VERSION 5.7 ;
  NOWIREEXTENSIONATPIN ON ;
  DIVIDERCHAR "/" ;
  BUSBITCHARS "[]" ;
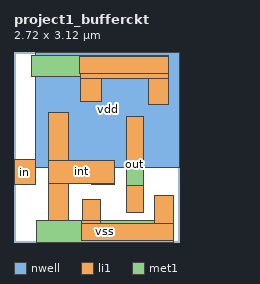
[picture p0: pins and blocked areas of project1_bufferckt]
MACRO project1_bufferckt
  CLASS BLOCK ;
  FOREIGN project1_bufferckt ;
  ORIGIN -2.150 2.430 ;
  SIZE 2.720 BY 3.120 ;
  PIN vdd
    ANTENNADIFFAREA 0.959400 ;
    PORT
      LAYER nwell ;
        RECT 2.510 -1.200 4.870 0.690 ;
      LAYER li1 ;
        RECT 3.230 0.340 4.690 0.620 ;
        RECT 3.240 0.260 4.690 0.340 ;
        RECT 3.240 -0.120 3.590 0.260 ;
        RECT 4.360 -0.180 4.690 0.260 ;
      LAYER met1 ;
        RECT 2.445 0.290 4.695 0.640 ;
    END
  END vdd
  PIN vss
    ANTENNADIFFAREA 0.336000 ;
    PORT
      LAYER li1 ;
        RECT 3.270 -2.080 3.570 -1.730 ;
        RECT 3.260 -2.120 3.570 -2.080 ;
        RECT 4.460 -2.120 4.770 -1.660 ;
        RECT 3.260 -2.410 4.770 -2.120 ;
      LAYER met1 ;
        RECT 2.520 -2.430 4.770 -2.080 ;
    END
  END vss
  PIN int
    ANTENNAGATEAREA 0.247500 ;
    ANTENNADIFFAREA 0.627000 ;
    PORT
      LAYER li1 ;
        RECT 2.710 -1.090 3.040 -0.300 ;
        RECT 2.710 -1.470 3.800 -1.090 ;
        RECT 2.710 -2.080 3.040 -1.470 ;
        RECT 3.430 -1.480 3.800 -1.470 ;
    END
  END int
  PIN in
    ANTENNAGATEAREA 0.247500 ;
    PORT
      LAYER li1 ;
        RECT 2.150 -1.490 2.510 -1.080 ;
    END
  END in
  PIN out
    ANTENNADIFFAREA 0.879000 ;
    PORT
      LAYER li1 ;
        RECT 3.990 -1.950 4.270 -0.370 ;
      LAYER met1 ;
        RECT 3.990 -1.510 4.270 -1.150 ;
    END
  END out
END project1_bufferckt
END LIBRARY

